! (c) 2009  Infineon Technologies AG, Munich
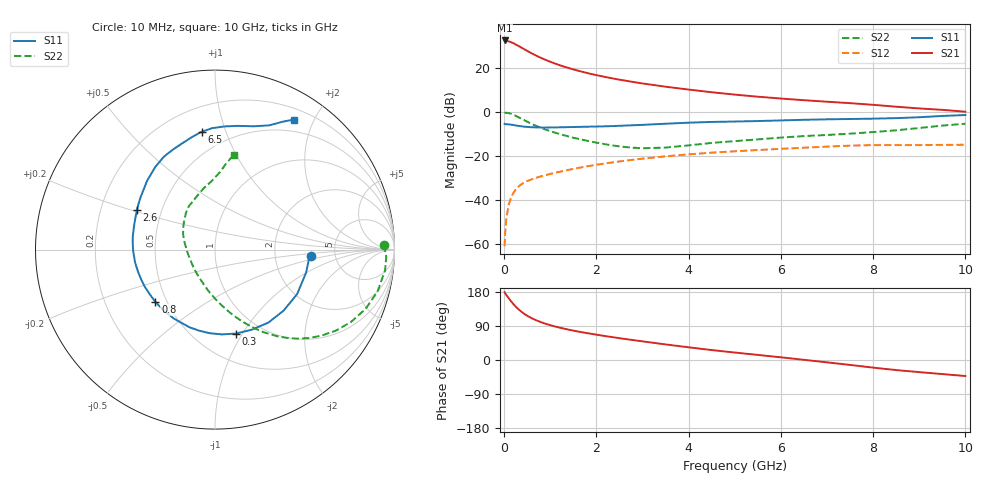
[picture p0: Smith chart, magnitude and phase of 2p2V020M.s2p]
! Infineon Technologies  Discrete & RF Semiconductors
! BFP420
! VCE =  2.0 V,  IC =  20 mA
! Common Emitter S-Parameters:  Nov 2009
# GHz  S  MA  R  50
!  f  S11  S21  S12  S22
! GHz  MAG  ANG  MAG  ANG  MAG  ANG  MAG  ANG
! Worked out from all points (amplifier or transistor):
!   46 points, 10 MHz to 10 GHz, reference 50 ohm
!   highest |S21| = 32.4 dB at 10 MHz (marker M1)
!   |S21| within 3 dB of that: start of sweep to 354 MHz
!   unconditionally stable (mu >= 1): 1.794 GHz to end of sweep
!   at 300 MHz: K = 0.31, MSG = 32.1 dB, |S12| = -34.1 dB
!   at 1.7 GHz: K = 0.98, MSG = 21.6 dB, |S12| = -25.1 dB
!   at 10 GHz: K = 1.07, MAG = 5.9 dB, |S12| = -14.9 dB
!   lowest NFmin = 1.23 dB at 900 MHz
!   S11 on the Smith chart (normalised r, x): 10 MHz: 3.27, -0.31; 300 MHz: 0.77, -0.94; 800 MHz: 0.43, -0.31; 2.6 GHz: 0.36, +0.21; 6.5 GHz: 0.36, +0.83; 10 GHz: 0.34, +1.73
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0.01  0.5353 -3.6  41.59 179.1  0.0009 97.7  0.9429 1.6
0.02  0.5256 -6.0  40.76 176.5  0.0017 90.2  0.955 -2.4
0.05  0.5235 -14.0  40.48 171.3  0.004 85.7  0.9546 -7.0
0.1  0.5204 -28.4  39.63 162.9  0.0079 79.1  0.9353 -14.5
0.15  0.5116 -41.5  37.98 154.9  0.0113 74.9  0.9015 -21.5
0.2  0.504 -53.8  36.02 147.7  0.0145 70.8  0.8591 -27.9
0.25  0.491 -65.3  33.77 141.0  0.0173 66.9  0.8129 -33.6
0.3  0.4822 -75.8  31.69 135.0  0.0197 64.0  0.7652 -38.7
0.4  0.4668 -93.6  27.63 125.0  0.0237 59.3  0.6754 -47.3
0.5  0.4554 -108.3  24.09 116.9  0.0269 56.5  0.5971 -54.1
0.6  0.4475 -120.4  21.16 110.1  0.0296 54.6  0.5325 -59.7
0.8  0.4418 -138.8  16.72 99.8  0.0345 52.8  0.4345 -68.6
1  0.4427 -152.4  13.68 91.9  0.0391 52.1  0.3654 -76.1
1.2  0.4457 -162.8  11.47 85.5  0.0437 51.7  0.3145 -82.9
1.7  0.458 177.8  8.073 73.0  0.0557 50.2  0.2323 -99.3
2.6  0.4879 153.3  5.148 55.8  0.0774 44.8  0.1603 -134.1
3.5  0.5384 134.7  3.719 41.1  0.098 37.5  0.1549 -174.9
5.5  0.6185 107.5  2.206 13.4  0.1362 19.7  0.2377 136.2
6.5  0.6608 96.5  1.837 0.5  0.1537 10.8  0.2825 121.0
7  0.6769 91.3  1.698 -6.2  0.1628 6.0  0.2987 113.6
8.5  0.7203 72.5  1.308 -26.6  0.1765 -10.9  0.3818 92.9
10  0.8469 58.8  1.007 -42.3  0.1796 -22.0  0.5379 78.8
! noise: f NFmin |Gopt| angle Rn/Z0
0.9  1.23  0.16  -154  0.13
1.8  1.51  0.24  -144  0.13
2.4  1.66  0.22  -141  0.15
3  1.69  0.3  -132  0.16
4  1.82  0.42  -115  0.23
5  2.28  0.48  -96  0.37
6  2.65  0.52  -86  0.56
